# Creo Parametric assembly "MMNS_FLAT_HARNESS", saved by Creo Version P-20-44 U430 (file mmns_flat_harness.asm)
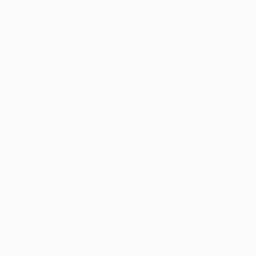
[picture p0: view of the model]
Units: millimeter Newton Second (mmNs); MM, TONNE, SECS

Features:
  1. datum plane "FLAT_HARNESS_RIGHT"
  2. datum plane "FLAT_HARNESS_TOP"
  3. datum plane "FLAT_HARNESS_FRONT"
  4. coordinate system

Other named items: FLAT_HARNESS_DEF_CSYS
